VERSION 5.7 ;
  NOWIREEXTENSIONATPIN ON ;
  DIVIDERCHAR "/" ;
  BUSBITCHARS "[]" ;
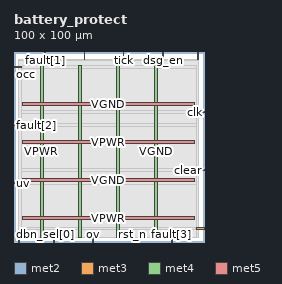
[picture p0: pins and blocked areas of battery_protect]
MACRO battery_protect
  CLASS BLOCK ;
  FOREIGN battery_protect ;
  ORIGIN 0.000 0.000 ;
  SIZE 100.000 BY 100.000 ;
  PIN chg_en
    DIRECTION OUTPUT TRISTATE ;
    USE SIGNAL ;
    PORT
      LAYER met2 ;
        RECT 20.790 0.000 21.070 4.000 ;
    END
  END chg_en
  PIN clear
    DIRECTION INPUT ;
    USE SIGNAL ;
    PORT
      LAYER met3 ;
        RECT 96.000 37.440 100.000 38.040 ;
    END
  END clear
  PIN clk
    DIRECTION INPUT ;
    USE SIGNAL ;
    PORT
      LAYER met3 ;
        RECT 96.000 68.040 100.000 68.640 ;
    END
  END clk
  PIN dbn_sel[0]
    DIRECTION INPUT ;
    USE SIGNAL ;
    PORT
      LAYER met2 ;
        RECT 2.390 0.000 2.670 4.000 ;
    END
  END dbn_sel[0]
  PIN dbn_sel[1]
    DIRECTION INPUT ;
    USE SIGNAL ;
    PORT
      LAYER met3 ;
        RECT 96.000 6.840 100.000 7.440 ;
    END
  END dbn_sel[1]
  PIN dsg_en
    DIRECTION OUTPUT TRISTATE ;
    USE SIGNAL ;
    PORT
      LAYER met2 ;
        RECT 78.290 96.000 78.570 100.000 ;
    END
  END dsg_en
  PIN fault[0]
    DIRECTION OUTPUT TRISTATE ;
    USE SIGNAL ;
    PORT
      LAYER met2 ;
        RECT 36.890 96.000 37.170 100.000 ;
    END
  END fault[0]
  PIN fault[1]
    DIRECTION OUTPUT TRISTATE ;
    USE SIGNAL ;
    PORT
      LAYER met2 ;
        RECT 16.190 96.000 16.470 100.000 ;
    END
  END fault[1]
  PIN fault[2]
    DIRECTION OUTPUT TRISTATE ;
    USE SIGNAL ;
    PORT
      LAYER met3 ;
        RECT 0.000 61.240 4.000 61.840 ;
    END
  END fault[2]
  PIN fault[3]
    DIRECTION OUTPUT TRISTATE ;
    USE SIGNAL ;
    PORT
      LAYER met2 ;
        RECT 82.890 0.000 83.170 4.000 ;
    END
  END fault[3]
  PIN occ
    DIRECTION INPUT ;
    USE SIGNAL ;
    PORT
      LAYER met3 ;
        RECT 0.000 91.840 4.000 92.440 ;
    END
  END occ
  PIN ocd
    DIRECTION INPUT ;
    USE SIGNAL ;
    PORT
      LAYER met2 ;
        RECT 96.690 96.000 96.970 100.000 ;
    END
  END ocd
  PIN ov
    DIRECTION INPUT ;
    USE SIGNAL ;
    PORT
      LAYER met2 ;
        RECT 41.490 0.000 41.770 4.000 ;
    END
  END ov
  PIN rst_n
    DIRECTION INPUT ;
    USE SIGNAL ;
    PORT
      LAYER met2 ;
        RECT 62.190 0.000 62.470 4.000 ;
    END
  END rst_n
  PIN tick
    DIRECTION INPUT ;
    USE SIGNAL ;
    PORT
      LAYER met2 ;
        RECT 57.590 96.000 57.870 100.000 ;
    END
  END tick
  PIN uv
    DIRECTION INPUT ;
    USE SIGNAL ;
    PORT
      LAYER met3 ;
        RECT 0.000 30.640 4.000 31.240 ;
    END
  END uv
  PIN VPWR
    DIRECTION INOUT ;
    USE POWER ;
    PORT
      LAYER met4 ;
        RECT 53.800 2.480 55.400 92.720 ;
    END
  END VPWR
  PIN VPWR
    DIRECTION INOUT ;
    USE POWER ;
    PORT
      LAYER met4 ;
        RECT 13.800 2.480 15.400 92.720 ;
    END
  END VPWR
  PIN VPWR
    DIRECTION INOUT ;
    USE POWER ;
    PORT
      LAYER met5 ;
        RECT 4.600 51.680 94.760 53.280 ;
    END
  END VPWR
  PIN VPWR
    DIRECTION INOUT ;
    USE POWER ;
    PORT
      LAYER met5 ;
        RECT 4.600 11.680 94.760 13.280 ;
    END
  END VPWR
  PIN VGND
    DIRECTION INOUT ;
    USE GROUND ;
    PORT
      LAYER met4 ;
        RECT 73.800 2.480 75.400 92.720 ;
    END
  END VGND
  PIN VGND
    DIRECTION INOUT ;
    USE GROUND ;
    PORT
      LAYER met4 ;
        RECT 33.800 2.480 35.400 92.720 ;
    END
  END VGND
  PIN VGND
    DIRECTION INOUT ;
    USE GROUND ;
    PORT
      LAYER met5 ;
        RECT 4.600 71.680 94.760 73.280 ;
    END
  END VGND
  PIN VGND
    DIRECTION INOUT ;
    USE GROUND ;
    PORT
      LAYER met5 ;
        RECT 4.600 31.680 94.760 33.280 ;
    END
  END VGND
  OBS
      LAYER li1 ;
        RECT 4.600 2.635 94.760 92.565 ;
      LAYER met1 ;
        RECT 2.830 2.480 96.990 92.720 ;
      LAYER met2 ;
        RECT 2.460 95.720 15.910 96.000 ;
        RECT 16.750 95.720 36.610 96.000 ;
        RECT 37.450 95.720 57.310 96.000 ;
        RECT 58.150 95.720 78.010 96.000 ;
        RECT 78.850 95.720 96.410 96.000 ;
        RECT 2.460 4.280 96.960 95.720 ;
        RECT 2.950 2.480 20.510 4.280 ;
        RECT 21.350 2.480 41.210 4.280 ;
        RECT 42.050 2.480 61.910 4.280 ;
        RECT 62.750 2.480 82.610 4.280 ;
        RECT 83.450 2.480 96.960 4.280 ;
      LAYER met3 ;
        RECT 4.400 91.440 96.000 92.645 ;
        RECT 4.000 69.040 96.000 91.440 ;
        RECT 4.000 67.640 95.600 69.040 ;
        RECT 4.000 62.240 96.000 67.640 ;
        RECT 4.400 60.840 96.000 62.240 ;
        RECT 4.000 38.440 96.000 60.840 ;
        RECT 4.000 37.040 95.600 38.440 ;
        RECT 4.000 31.640 96.000 37.040 ;
        RECT 4.400 30.240 96.000 31.640 ;
        RECT 4.000 7.840 96.000 30.240 ;
        RECT 4.000 6.440 95.600 7.840 ;
        RECT 4.000 2.555 96.000 6.440 ;
  END
END battery_protect
END LIBRARY

